VERSION 5.7 ;
  NOWIREEXTENSIONATPIN ON ;
  DIVIDERCHAR "/" ;
  BUSBITCHARS "[]" ;
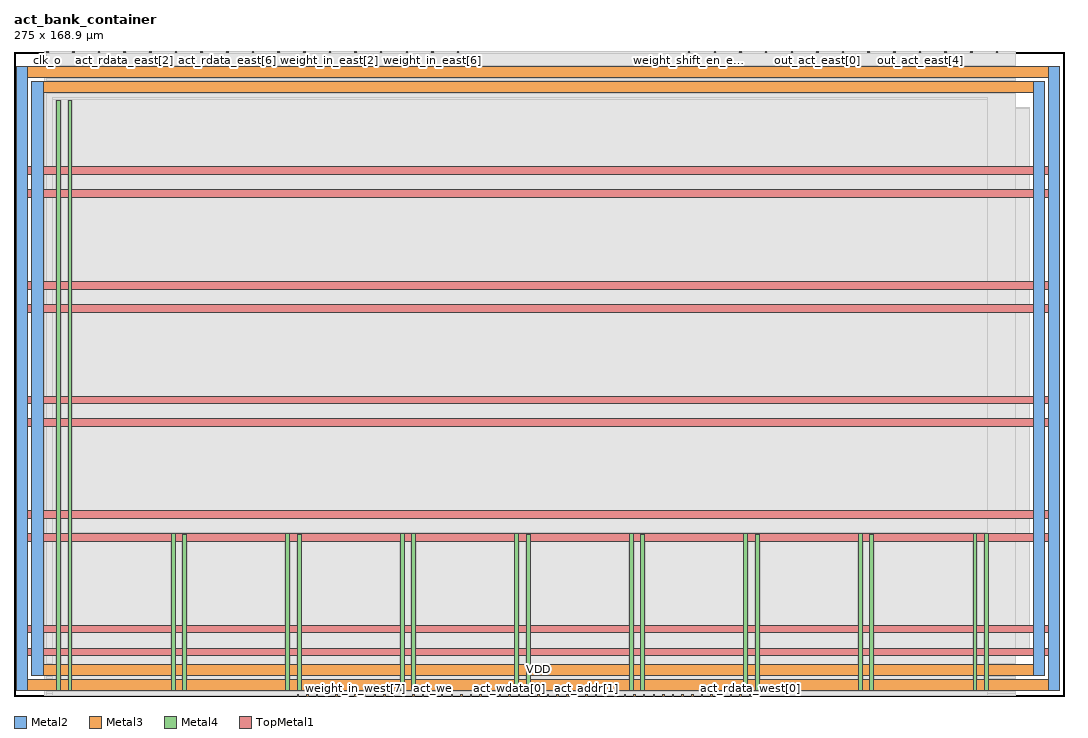
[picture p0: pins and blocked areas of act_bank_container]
MACRO act_bank_container
  CLASS BLOCK ;
  FOREIGN act_bank_container ;
  ORIGIN 0.000 0.000 ;
  SIZE 275.000 BY 168.900 ;
  PIN VDD
    DIRECTION INOUT ;
    USE POWER ;
    PORT
      LAYER Metal2 ;
        RECT 4.640 5.340 7.640 160.980 ;
    END
    PORT
      LAYER Metal2 ;
        RECT 266.920 5.340 269.920 160.980 ;
    END
    PORT
      LAYER Metal3 ;
        RECT 4.640 5.340 269.920 8.340 ;
    END
    PORT
      LAYER Metal3 ;
        RECT 4.640 157.980 269.920 160.980 ;
    END
    PORT
      LAYER Metal4 ;
        RECT 11.180 1.340 12.180 155.960 ;
    END
    PORT
      LAYER Metal4 ;
        RECT 41.180 1.340 42.180 42.560 ;
    END
    PORT
      LAYER Metal4 ;
        RECT 71.180 1.340 72.180 42.560 ;
    END
    PORT
      LAYER Metal4 ;
        RECT 101.180 1.340 102.180 42.560 ;
    END
    PORT
      LAYER Metal4 ;
        RECT 131.180 1.340 132.180 42.560 ;
    END
    PORT
      LAYER Metal4 ;
        RECT 161.180 1.340 162.180 42.660 ;
    END
    PORT
      LAYER Metal4 ;
        RECT 191.180 1.340 192.180 42.560 ;
    END
    PORT
      LAYER Metal4 ;
        RECT 221.180 1.340 222.180 42.560 ;
    END
    PORT
      LAYER Metal4 ;
        RECT 251.180 1.340 252.180 42.660 ;
    END
    PORT
      LAYER TopMetal1 ;
        RECT 0.640 10.560 273.920 12.560 ;
    END
    PORT
      LAYER TopMetal1 ;
        RECT 0.640 40.560 273.920 42.560 ;
    END
    PORT
      LAYER TopMetal1 ;
        RECT 0.640 70.560 273.920 72.560 ;
    END
    PORT
      LAYER TopMetal1 ;
        RECT 0.640 100.560 273.920 102.560 ;
    END
    PORT
      LAYER TopMetal1 ;
        RECT 0.640 130.560 273.920 132.560 ;
    END
  END VDD
  PIN VSS
    DIRECTION INOUT ;
    USE GROUND ;
    PORT
      LAYER Metal2 ;
        RECT 0.640 1.340 3.640 164.980 ;
    END
    PORT
      LAYER Metal2 ;
        RECT 270.920 1.340 273.920 164.980 ;
    END
    PORT
      LAYER Metal3 ;
        RECT 0.640 1.340 273.920 4.340 ;
    END
    PORT
      LAYER Metal3 ;
        RECT 0.640 161.980 273.920 164.980 ;
    END
    PORT
      LAYER Metal4 ;
        RECT 14.180 1.340 15.180 155.960 ;
    END
    PORT
      LAYER Metal4 ;
        RECT 44.180 1.340 45.180 42.420 ;
    END
    PORT
      LAYER Metal4 ;
        RECT 74.180 1.340 75.180 42.420 ;
    END
    PORT
      LAYER Metal4 ;
        RECT 104.180 1.340 105.180 42.660 ;
    END
    PORT
      LAYER Metal4 ;
        RECT 134.180 1.340 135.180 42.420 ;
    END
    PORT
      LAYER Metal4 ;
        RECT 164.180 1.340 165.180 42.420 ;
    END
    PORT
      LAYER Metal4 ;
        RECT 194.180 1.340 195.180 42.420 ;
    END
    PORT
      LAYER Metal4 ;
        RECT 224.180 1.340 225.180 42.420 ;
    END
    PORT
      LAYER Metal4 ;
        RECT 254.180 1.340 255.180 42.660 ;
    END
    PORT
      LAYER TopMetal1 ;
        RECT 0.640 16.560 273.920 18.560 ;
    END
    PORT
      LAYER TopMetal1 ;
        RECT 0.640 46.560 273.920 48.560 ;
    END
    PORT
      LAYER TopMetal1 ;
        RECT 0.640 76.560 273.920 78.560 ;
    END
    PORT
      LAYER TopMetal1 ;
        RECT 0.640 106.560 273.920 108.560 ;
    END
    PORT
      LAYER TopMetal1 ;
        RECT 0.640 136.560 273.920 138.560 ;
    END
  END VSS
  PIN act_addr[0]
    DIRECTION INPUT ;
    USE SIGNAL ;
    ANTENNAGATEAREA 0.109200 ;
    PORT
      LAYER Metal3 ;
        RECT 152.260 0.000 152.660 0.400 ;
    END
  END act_addr[0]
  PIN act_addr[1]
    DIRECTION INPUT ;
    USE SIGNAL ;
    ANTENNAGATEAREA 0.109200 ;
    PORT
      LAYER Metal3 ;
        RECT 149.740 0.000 150.140 0.400 ;
    END
  END act_addr[1]
  PIN act_addr[2]
    DIRECTION INPUT ;
    USE SIGNAL ;
    ANTENNAGATEAREA 0.109200 ;
    PORT
      LAYER Metal3 ;
        RECT 147.220 0.000 147.620 0.400 ;
    END
  END act_addr[2]
  PIN act_addr[3]
    DIRECTION INPUT ;
    USE SIGNAL ;
    ANTENNAGATEAREA 0.109200 ;
    PORT
      LAYER Metal3 ;
        RECT 144.700 0.000 145.100 0.400 ;
    END
  END act_addr[3]
  PIN act_addr[4]
    DIRECTION INPUT ;
    USE SIGNAL ;
    ANTENNAGATEAREA 0.109200 ;
    PORT
      LAYER Metal3 ;
        RECT 142.180 0.000 142.580 0.400 ;
    END
  END act_addr[4]
  PIN act_addr[5]
    DIRECTION INPUT ;
    USE SIGNAL ;
    ANTENNAGATEAREA 0.109200 ;
    PORT
      LAYER Metal3 ;
        RECT 139.660 0.000 140.060 0.400 ;
    END
  END act_addr[5]
  PIN act_addr[6]
    DIRECTION INPUT ;
    USE SIGNAL ;
    ANTENNAGATEAREA 0.109200 ;
    PORT
      LAYER Metal3 ;
        RECT 137.140 0.000 137.540 0.400 ;
    END
  END act_addr[6]
  PIN act_addr[7]
    DIRECTION INPUT ;
    USE SIGNAL ;
    ANTENNAGATEAREA 0.109200 ;
    PORT
      LAYER Metal3 ;
        RECT 134.620 0.000 135.020 0.400 ;
    END
  END act_addr[7]
  PIN act_addr[8]
    DIRECTION INPUT ;
    USE SIGNAL ;
    ANTENNAGATEAREA 0.109200 ;
    PORT
      LAYER Metal3 ;
        RECT 132.100 0.000 132.500 0.400 ;
    END
  END act_addr[8]
  PIN act_rdata_east[0]
    DIRECTION OUTPUT ;
    USE SIGNAL ;
    ANTENNADIFFAREA 0.708600 ;
    PORT
      LAYER Metal3 ;
        RECT 15.340 168.500 15.740 168.900 ;
    END
  END act_rdata_east[0]
  PIN act_rdata_east[1]
    DIRECTION OUTPUT ;
    USE SIGNAL ;
    ANTENNADIFFAREA 0.708600 ;
    PORT
      LAYER Metal3 ;
        RECT 22.060 168.500 22.460 168.900 ;
    END
  END act_rdata_east[1]
  PIN act_rdata_east[2]
    DIRECTION OUTPUT ;
    USE SIGNAL ;
    ANTENNADIFFAREA 0.708600 ;
    PORT
      LAYER Metal3 ;
        RECT 28.780 168.500 29.180 168.900 ;
    END
  END act_rdata_east[2]
  PIN act_rdata_east[3]
    DIRECTION OUTPUT ;
    USE SIGNAL ;
    ANTENNADIFFAREA 0.708600 ;
    PORT
      LAYER Metal3 ;
        RECT 35.500 168.500 35.900 168.900 ;
    END
  END act_rdata_east[3]
  PIN act_rdata_east[4]
    DIRECTION OUTPUT ;
    USE SIGNAL ;
    ANTENNADIFFAREA 0.708600 ;
    PORT
      LAYER Metal3 ;
        RECT 42.220 168.500 42.620 168.900 ;
    END
  END act_rdata_east[4]
  PIN act_rdata_east[5]
    DIRECTION OUTPUT ;
    USE SIGNAL ;
    ANTENNADIFFAREA 0.708600 ;
    PORT
      LAYER Metal3 ;
        RECT 48.940 168.500 49.340 168.900 ;
    END
  END act_rdata_east[5]
  PIN act_rdata_east[6]
    DIRECTION OUTPUT ;
    USE SIGNAL ;
    ANTENNADIFFAREA 0.708600 ;
    PORT
      LAYER Metal3 ;
        RECT 55.660 168.500 56.060 168.900 ;
    END
  END act_rdata_east[6]
  PIN act_rdata_east[7]
    DIRECTION OUTPUT ;
    USE SIGNAL ;
    ANTENNADIFFAREA 0.708600 ;
    PORT
      LAYER Metal3 ;
        RECT 62.380 168.500 62.780 168.900 ;
    END
  END act_rdata_east[7]
  PIN act_rdata_west[0]
    DIRECTION OUTPUT ;
    USE SIGNAL ;
    ANTENNADIFFAREA 0.708600 ;
    PORT
      LAYER Metal3 ;
        RECT 192.580 0.000 192.980 0.400 ;
    END
  END act_rdata_west[0]
  PIN act_rdata_west[1]
    DIRECTION OUTPUT ;
    USE SIGNAL ;
    ANTENNADIFFAREA 0.708600 ;
    PORT
      LAYER Metal3 ;
        RECT 190.060 0.000 190.460 0.400 ;
    END
  END act_rdata_west[1]
  PIN act_rdata_west[2]
    DIRECTION OUTPUT ;
    USE SIGNAL ;
    ANTENNADIFFAREA 0.708600 ;
    PORT
      LAYER Metal3 ;
        RECT 187.540 0.000 187.940 0.400 ;
    END
  END act_rdata_west[2]
  PIN act_rdata_west[3]
    DIRECTION OUTPUT ;
    USE SIGNAL ;
    ANTENNADIFFAREA 0.708600 ;
    PORT
      LAYER Metal3 ;
        RECT 185.020 0.000 185.420 0.400 ;
    END
  END act_rdata_west[3]
  PIN act_rdata_west[4]
    DIRECTION OUTPUT ;
    USE SIGNAL ;
    ANTENNADIFFAREA 0.708600 ;
    PORT
      LAYER Metal3 ;
        RECT 182.500 0.000 182.900 0.400 ;
    END
  END act_rdata_west[4]
  PIN act_rdata_west[5]
    DIRECTION OUTPUT ;
    USE SIGNAL ;
    ANTENNADIFFAREA 0.708600 ;
    PORT
      LAYER Metal3 ;
        RECT 179.980 0.000 180.380 0.400 ;
    END
  END act_rdata_west[5]
  PIN act_rdata_west[6]
    DIRECTION OUTPUT ;
    USE SIGNAL ;
    ANTENNADIFFAREA 0.708600 ;
    PORT
      LAYER Metal3 ;
        RECT 177.460 0.000 177.860 0.400 ;
    END
  END act_rdata_west[6]
  PIN act_rdata_west[7]
    DIRECTION OUTPUT ;
    USE SIGNAL ;
    ANTENNADIFFAREA 0.708600 ;
    PORT
      LAYER Metal3 ;
        RECT 174.940 0.000 175.340 0.400 ;
    END
  END act_rdata_west[7]
  PIN act_wdata[0]
    DIRECTION INPUT ;
    USE SIGNAL ;
    ANTENNAGATEAREA 0.109200 ;
    PORT
      LAYER Metal3 ;
        RECT 129.580 0.000 129.980 0.400 ;
    END
  END act_wdata[0]
  PIN act_wdata[1]
    DIRECTION INPUT ;
    USE SIGNAL ;
    ANTENNAGATEAREA 0.109200 ;
    PORT
      LAYER Metal3 ;
        RECT 127.060 0.000 127.460 0.400 ;
    END
  END act_wdata[1]
  PIN act_wdata[2]
    DIRECTION INPUT ;
    USE SIGNAL ;
    ANTENNAGATEAREA 0.109200 ;
    PORT
      LAYER Metal3 ;
        RECT 124.540 0.000 124.940 0.400 ;
    END
  END act_wdata[2]
  PIN act_wdata[3]
    DIRECTION INPUT ;
    USE SIGNAL ;
    ANTENNAGATEAREA 0.109200 ;
    PORT
      LAYER Metal3 ;
        RECT 122.020 0.000 122.420 0.400 ;
    END
  END act_wdata[3]
  PIN act_wdata[4]
    DIRECTION INPUT ;
    USE SIGNAL ;
    ANTENNAGATEAREA 0.109200 ;
    PORT
      LAYER Metal3 ;
        RECT 119.500 0.000 119.900 0.400 ;
    END
  END act_wdata[4]
  PIN act_wdata[5]
    DIRECTION INPUT ;
    USE SIGNAL ;
    ANTENNAGATEAREA 0.109200 ;
    PORT
      LAYER Metal3 ;
        RECT 116.980 0.000 117.380 0.400 ;
    END
  END act_wdata[5]
  PIN act_wdata[6]
    DIRECTION INPUT ;
    USE SIGNAL ;
    ANTENNAGATEAREA 0.109200 ;
    PORT
      LAYER Metal3 ;
        RECT 114.460 0.000 114.860 0.400 ;
    END
  END act_wdata[6]
  PIN act_wdata[7]
    DIRECTION INPUT ;
    USE SIGNAL ;
    ANTENNAGATEAREA 0.109200 ;
    PORT
      LAYER Metal3 ;
        RECT 111.940 0.000 112.340 0.400 ;
    END
  END act_wdata[7]
  PIN act_we
    DIRECTION INPUT ;
    USE SIGNAL ;
    ANTENNAGATEAREA 0.109200 ;
    PORT
      LAYER Metal3 ;
        RECT 109.420 0.000 109.820 0.400 ;
    END
  END act_we
  PIN clk_i
    DIRECTION INPUT ;
    USE SIGNAL ;
    ANTENNAGATEAREA 0.381550 ;
    PORT
      LAYER Metal3 ;
        RECT 74.140 0.000 74.540 0.400 ;
    END
  END clk_i
  PIN clk_o
    DIRECTION OUTPUT ;
    USE SIGNAL ;
    ANTENNADIFFAREA 0.708600 ;
    PORT
      LAYER Metal3 ;
        RECT 8.620 168.500 9.020 168.900 ;
    END
  END clk_o
  PIN out_act_east[0]
    DIRECTION INPUT ;
    USE SIGNAL ;
    ANTENNAGATEAREA 0.180700 ;
    PORT
      LAYER Metal3 ;
        RECT 210.220 168.500 210.620 168.900 ;
    END
  END out_act_east[0]
  PIN out_act_east[1]
    DIRECTION INPUT ;
    USE SIGNAL ;
    ANTENNAGATEAREA 0.180700 ;
    PORT
      LAYER Metal3 ;
        RECT 216.940 168.500 217.340 168.900 ;
    END
  END out_act_east[1]
  PIN out_act_east[2]
    DIRECTION INPUT ;
    USE SIGNAL ;
    ANTENNAGATEAREA 0.180700 ;
    ANTENNADIFFAREA 2.015400 ;
    PORT
      LAYER Metal3 ;
        RECT 223.660 168.500 224.060 168.900 ;
    END
  END out_act_east[2]
  PIN out_act_east[3]
    DIRECTION INPUT ;
    USE SIGNAL ;
    ANTENNAGATEAREA 0.180700 ;
    PORT
      LAYER Metal3 ;
        RECT 230.380 168.500 230.780 168.900 ;
    END
  END out_act_east[3]
  PIN out_act_east[4]
    DIRECTION INPUT ;
    USE SIGNAL ;
    ANTENNAGATEAREA 0.180700 ;
    PORT
      LAYER Metal3 ;
        RECT 237.100 168.500 237.500 168.900 ;
    END
  END out_act_east[4]
  PIN out_act_east[5]
    DIRECTION INPUT ;
    USE SIGNAL ;
    ANTENNAGATEAREA 0.180700 ;
    PORT
      LAYER Metal3 ;
        RECT 243.820 168.500 244.220 168.900 ;
    END
  END out_act_east[5]
  PIN out_act_east[6]
    DIRECTION INPUT ;
    USE SIGNAL ;
    ANTENNAGATEAREA 0.180700 ;
    PORT
      LAYER Metal3 ;
        RECT 250.540 168.500 250.940 168.900 ;
    END
  END out_act_east[6]
  PIN out_act_east[7]
    DIRECTION INPUT ;
    USE SIGNAL ;
    ANTENNAGATEAREA 0.180700 ;
    PORT
      LAYER Metal3 ;
        RECT 257.260 168.500 257.660 168.900 ;
    END
  END out_act_east[7]
  PIN out_act_west[0]
    DIRECTION OUTPUT ;
    USE SIGNAL ;
    ANTENNADIFFAREA 0.708600 ;
    PORT
      LAYER Metal3 ;
        RECT 172.420 0.000 172.820 0.400 ;
    END
  END out_act_west[0]
  PIN out_act_west[1]
    DIRECTION OUTPUT ;
    USE SIGNAL ;
    ANTENNADIFFAREA 0.708600 ;
    PORT
      LAYER Metal3 ;
        RECT 169.900 0.000 170.300 0.400 ;
    END
  END out_act_west[1]
  PIN out_act_west[2]
    DIRECTION OUTPUT ;
    USE SIGNAL ;
    ANTENNADIFFAREA 0.708600 ;
    PORT
      LAYER Metal3 ;
        RECT 167.380 0.000 167.780 0.400 ;
    END
  END out_act_west[2]
  PIN out_act_west[3]
    DIRECTION OUTPUT ;
    USE SIGNAL ;
    ANTENNADIFFAREA 0.708600 ;
    PORT
      LAYER Metal3 ;
        RECT 164.860 0.000 165.260 0.400 ;
    END
  END out_act_west[3]
  PIN out_act_west[4]
    DIRECTION OUTPUT ;
    USE SIGNAL ;
    ANTENNADIFFAREA 0.708600 ;
    PORT
      LAYER Metal3 ;
        RECT 162.340 0.000 162.740 0.400 ;
    END
  END out_act_west[4]
  PIN out_act_west[5]
    DIRECTION OUTPUT ;
    USE SIGNAL ;
    ANTENNADIFFAREA 0.708600 ;
    PORT
      LAYER Metal3 ;
        RECT 159.820 0.000 160.220 0.400 ;
    END
  END out_act_west[5]
  PIN out_act_west[6]
    DIRECTION OUTPUT ;
    USE SIGNAL ;
    ANTENNADIFFAREA 0.708600 ;
    PORT
      LAYER Metal3 ;
        RECT 157.300 0.000 157.700 0.400 ;
    END
  END out_act_west[6]
  PIN out_act_west[7]
    DIRECTION OUTPUT ;
    USE SIGNAL ;
    ANTENNADIFFAREA 0.708600 ;
    PORT
      LAYER Metal3 ;
        RECT 154.780 0.000 155.180 0.400 ;
    END
  END out_act_west[7]
  PIN weight_in_east[0]
    DIRECTION OUTPUT ;
    USE SIGNAL ;
    ANTENNADIFFAREA 0.708600 ;
    PORT
      LAYER Metal3 ;
        RECT 69.100 168.500 69.500 168.900 ;
    END
  END weight_in_east[0]
  PIN weight_in_east[1]
    DIRECTION OUTPUT ;
    USE SIGNAL ;
    ANTENNADIFFAREA 0.708600 ;
    PORT
      LAYER Metal3 ;
        RECT 75.820 168.500 76.220 168.900 ;
    END
  END weight_in_east[1]
  PIN weight_in_east[2]
    DIRECTION OUTPUT ;
    USE SIGNAL ;
    ANTENNADIFFAREA 0.708600 ;
    PORT
      LAYER Metal3 ;
        RECT 82.540 168.500 82.940 168.900 ;
    END
  END weight_in_east[2]
  PIN weight_in_east[3]
    DIRECTION OUTPUT ;
    USE SIGNAL ;
    ANTENNADIFFAREA 0.708600 ;
    PORT
      LAYER Metal3 ;
        RECT 89.260 168.500 89.660 168.900 ;
    END
  END weight_in_east[3]
  PIN weight_in_east[4]
    DIRECTION OUTPUT ;
    USE SIGNAL ;
    ANTENNADIFFAREA 0.708600 ;
    PORT
      LAYER Metal3 ;
        RECT 95.980 168.500 96.380 168.900 ;
    END
  END weight_in_east[4]
  PIN weight_in_east[5]
    DIRECTION OUTPUT ;
    USE SIGNAL ;
    ANTENNADIFFAREA 0.708600 ;
    PORT
      LAYER Metal3 ;
        RECT 102.700 168.500 103.100 168.900 ;
    END
  END weight_in_east[5]
  PIN weight_in_east[6]
    DIRECTION OUTPUT ;
    USE SIGNAL ;
    ANTENNADIFFAREA 0.708600 ;
    PORT
      LAYER Metal3 ;
        RECT 109.420 168.500 109.820 168.900 ;
    END
  END weight_in_east[6]
  PIN weight_in_east[7]
    DIRECTION OUTPUT ;
    USE SIGNAL ;
    ANTENNADIFFAREA 0.708600 ;
    PORT
      LAYER Metal3 ;
        RECT 116.140 168.500 116.540 168.900 ;
    END
  END weight_in_east[7]
  PIN weight_in_west[0]
    DIRECTION INPUT ;
    USE SIGNAL ;
    ANTENNAGATEAREA 0.180700 ;
    PORT
      LAYER Metal3 ;
        RECT 106.900 0.000 107.300 0.400 ;
    END
  END weight_in_west[0]
  PIN weight_in_west[1]
    DIRECTION INPUT ;
    USE SIGNAL ;
    ANTENNAGATEAREA 0.180700 ;
    PORT
      LAYER Metal3 ;
        RECT 104.380 0.000 104.780 0.400 ;
    END
  END weight_in_west[1]
  PIN weight_in_west[2]
    DIRECTION INPUT ;
    USE SIGNAL ;
    ANTENNAGATEAREA 0.180700 ;
    PORT
      LAYER Metal3 ;
        RECT 101.860 0.000 102.260 0.400 ;
    END
  END weight_in_west[2]
  PIN weight_in_west[3]
    DIRECTION INPUT ;
    USE SIGNAL ;
    ANTENNAGATEAREA 0.180700 ;
    PORT
      LAYER Metal3 ;
        RECT 99.340 0.000 99.740 0.400 ;
    END
  END weight_in_west[3]
  PIN weight_in_west[4]
    DIRECTION INPUT ;
    USE SIGNAL ;
    ANTENNAGATEAREA 0.180700 ;
    PORT
      LAYER Metal3 ;
        RECT 96.820 0.000 97.220 0.400 ;
    END
  END weight_in_west[4]
  PIN weight_in_west[5]
    DIRECTION INPUT ;
    USE SIGNAL ;
    ANTENNAGATEAREA 0.180700 ;
    PORT
      LAYER Metal3 ;
        RECT 94.300 0.000 94.700 0.400 ;
    END
  END weight_in_west[5]
  PIN weight_in_west[6]
    DIRECTION INPUT ;
    USE SIGNAL ;
    ANTENNAGATEAREA 0.180700 ;
    PORT
      LAYER Metal3 ;
        RECT 91.780 0.000 92.180 0.400 ;
    END
  END weight_in_west[6]
  PIN weight_in_west[7]
    DIRECTION INPUT ;
    USE SIGNAL ;
    ANTENNAGATEAREA 0.180700 ;
    PORT
      LAYER Metal3 ;
        RECT 89.260 0.000 89.660 0.400 ;
    END
  END weight_in_west[7]
  PIN weight_shift_en_east
    DIRECTION OUTPUT ;
    USE SIGNAL ;
    ANTENNADIFFAREA 0.708600 ;
    PORT
      LAYER Metal3 ;
        RECT 176.620 168.500 177.020 168.900 ;
    END
  END weight_shift_en_east
  PIN weight_shift_en_west
    DIRECTION INPUT ;
    USE SIGNAL ;
    ANTENNAGATEAREA 0.180700 ;
    PORT
      LAYER Metal3 ;
        RECT 86.740 0.000 87.140 0.400 ;
    END
  END weight_shift_en_west
  PIN xbar_sel_east[0]
    DIRECTION OUTPUT ;
    USE SIGNAL ;
    ANTENNADIFFAREA 0.708600 ;
    PORT
      LAYER Metal3 ;
        RECT 183.340 168.500 183.740 168.900 ;
    END
  END xbar_sel_east[0]
  PIN xbar_sel_east[1]
    DIRECTION OUTPUT ;
    USE SIGNAL ;
    ANTENNADIFFAREA 0.708600 ;
    PORT
      LAYER Metal3 ;
        RECT 190.060 168.500 190.460 168.900 ;
    END
  END xbar_sel_east[1]
  PIN xbar_sel_east[2]
    DIRECTION OUTPUT ;
    USE SIGNAL ;
    ANTENNADIFFAREA 0.708600 ;
    PORT
      LAYER Metal3 ;
        RECT 196.780 168.500 197.180 168.900 ;
    END
  END xbar_sel_east[2]
  PIN xbar_sel_east[3]
    DIRECTION OUTPUT ;
    USE SIGNAL ;
    ANTENNADIFFAREA 0.708600 ;
    PORT
      LAYER Metal3 ;
        RECT 203.500 168.500 203.900 168.900 ;
    END
  END xbar_sel_east[3]
  PIN xbar_sel_west[0]
    DIRECTION INPUT ;
    USE SIGNAL ;
    ANTENNAGATEAREA 0.180700 ;
    PORT
      LAYER Metal3 ;
        RECT 84.220 0.000 84.620 0.400 ;
    END
  END xbar_sel_west[0]
  PIN xbar_sel_west[1]
    DIRECTION INPUT ;
    USE SIGNAL ;
    ANTENNAGATEAREA 0.180700 ;
    PORT
      LAYER Metal3 ;
        RECT 81.700 0.000 82.100 0.400 ;
    END
  END xbar_sel_west[1]
  PIN xbar_sel_west[2]
    DIRECTION INPUT ;
    USE SIGNAL ;
    ANTENNAGATEAREA 0.180700 ;
    PORT
      LAYER Metal3 ;
        RECT 79.180 0.000 79.580 0.400 ;
    END
  END xbar_sel_west[2]
  PIN xbar_sel_west[3]
    DIRECTION INPUT ;
    USE SIGNAL ;
    ANTENNAGATEAREA 0.180700 ;
    PORT
      LAYER Metal3 ;
        RECT 76.660 0.000 77.060 0.400 ;
    END
  END xbar_sel_west[3]
  OBS
      LAYER GatPoly ;
        RECT 8.640 11.190 265.920 154.040 ;
      LAYER Metal1 ;
        RECT 8.640 11.120 265.920 153.995 ;
      LAYER Metal2 ;
        RECT 8.060 0.055 262.185 168.845 ;
      LAYER Metal3 ;
        RECT 9.230 168.290 15.130 168.800 ;
        RECT 15.950 168.290 21.850 168.800 ;
        RECT 22.670 168.290 28.570 168.800 ;
        RECT 29.390 168.290 35.290 168.800 ;
        RECT 36.110 168.290 42.010 168.800 ;
        RECT 42.830 168.290 48.730 168.800 ;
        RECT 49.550 168.290 55.450 168.800 ;
        RECT 56.270 168.290 62.170 168.800 ;
        RECT 62.990 168.290 68.890 168.800 ;
        RECT 69.710 168.290 75.610 168.800 ;
        RECT 76.430 168.290 82.330 168.800 ;
        RECT 83.150 168.290 89.050 168.800 ;
        RECT 89.870 168.290 95.770 168.800 ;
        RECT 96.590 168.290 102.490 168.800 ;
        RECT 103.310 168.290 109.210 168.800 ;
        RECT 110.030 168.290 115.930 168.800 ;
        RECT 116.750 168.290 176.410 168.800 ;
        RECT 177.230 168.290 183.130 168.800 ;
        RECT 183.950 168.290 189.850 168.800 ;
        RECT 190.670 168.290 196.570 168.800 ;
        RECT 197.390 168.290 203.290 168.800 ;
        RECT 204.110 168.290 210.010 168.800 ;
        RECT 210.830 168.290 216.730 168.800 ;
        RECT 217.550 168.290 223.450 168.800 ;
        RECT 224.270 168.290 230.170 168.800 ;
        RECT 230.990 168.290 236.890 168.800 ;
        RECT 237.710 168.290 243.610 168.800 ;
        RECT 244.430 168.290 250.330 168.800 ;
        RECT 251.150 168.290 257.050 168.800 ;
        RECT 257.870 168.290 262.225 168.800 ;
        RECT 8.495 165.190 262.225 168.290 ;
        RECT 8.495 161.190 262.225 161.770 ;
        RECT 8.495 8.550 262.225 157.770 ;
        RECT 8.495 4.550 262.225 5.130 ;
        RECT 8.495 0.610 262.225 1.130 ;
        RECT 8.495 0.095 73.930 0.610 ;
        RECT 74.750 0.095 76.450 0.610 ;
        RECT 77.270 0.095 78.970 0.610 ;
        RECT 79.790 0.095 81.490 0.610 ;
        RECT 82.310 0.095 84.010 0.610 ;
        RECT 84.830 0.095 86.530 0.610 ;
        RECT 87.350 0.095 89.050 0.610 ;
        RECT 89.870 0.095 91.570 0.610 ;
        RECT 92.390 0.095 94.090 0.610 ;
        RECT 94.910 0.095 96.610 0.610 ;
        RECT 97.430 0.095 99.130 0.610 ;
        RECT 99.950 0.095 101.650 0.610 ;
        RECT 102.470 0.095 104.170 0.610 ;
        RECT 104.990 0.095 106.690 0.610 ;
        RECT 107.510 0.095 109.210 0.610 ;
        RECT 110.030 0.095 111.730 0.610 ;
        RECT 112.550 0.095 114.250 0.610 ;
        RECT 115.070 0.095 116.770 0.610 ;
        RECT 117.590 0.095 119.290 0.610 ;
        RECT 120.110 0.095 121.810 0.610 ;
        RECT 122.630 0.095 124.330 0.610 ;
        RECT 125.150 0.095 126.850 0.610 ;
        RECT 127.670 0.095 129.370 0.610 ;
        RECT 130.190 0.095 131.890 0.610 ;
        RECT 132.710 0.095 134.410 0.610 ;
        RECT 135.230 0.095 136.930 0.610 ;
        RECT 137.750 0.095 139.450 0.610 ;
        RECT 140.270 0.095 141.970 0.610 ;
        RECT 142.790 0.095 144.490 0.610 ;
        RECT 145.310 0.095 147.010 0.610 ;
        RECT 147.830 0.095 149.530 0.610 ;
        RECT 150.350 0.095 152.050 0.610 ;
        RECT 152.870 0.095 154.570 0.610 ;
        RECT 155.390 0.095 157.090 0.610 ;
        RECT 157.910 0.095 159.610 0.610 ;
        RECT 160.430 0.095 162.130 0.610 ;
        RECT 162.950 0.095 164.650 0.610 ;
        RECT 165.470 0.095 167.170 0.610 ;
        RECT 167.990 0.095 169.690 0.610 ;
        RECT 170.510 0.095 172.210 0.610 ;
        RECT 173.030 0.095 174.730 0.610 ;
        RECT 175.550 0.095 177.250 0.610 ;
        RECT 178.070 0.095 179.770 0.610 ;
        RECT 180.590 0.095 182.290 0.610 ;
        RECT 183.110 0.095 184.810 0.610 ;
        RECT 185.630 0.095 187.330 0.610 ;
        RECT 188.150 0.095 189.850 0.610 ;
        RECT 190.670 0.095 192.370 0.610 ;
        RECT 193.190 0.095 262.225 0.610 ;
      LAYER Metal4 ;
        RECT 9.980 156.170 254.980 156.805 ;
        RECT 9.980 1.130 10.970 156.170 ;
        RECT 12.390 1.130 13.970 156.170 ;
        RECT 15.390 42.870 254.980 156.170 ;
        RECT 15.390 42.770 103.970 42.870 ;
        RECT 15.390 1.130 40.970 42.770 ;
        RECT 42.390 42.630 70.970 42.770 ;
        RECT 42.390 1.130 43.970 42.630 ;
        RECT 45.390 1.130 70.970 42.630 ;
        RECT 72.390 42.630 100.970 42.770 ;
        RECT 72.390 1.130 73.970 42.630 ;
        RECT 75.390 1.130 100.970 42.630 ;
        RECT 102.390 1.130 103.970 42.770 ;
        RECT 105.390 42.770 160.970 42.870 ;
        RECT 105.390 1.130 130.970 42.770 ;
        RECT 132.390 42.630 160.970 42.770 ;
        RECT 132.390 1.130 133.970 42.630 ;
        RECT 135.390 1.130 160.970 42.630 ;
        RECT 162.390 42.770 250.970 42.870 ;
        RECT 162.390 42.630 190.970 42.770 ;
        RECT 162.390 1.130 163.970 42.630 ;
        RECT 165.390 1.130 190.970 42.630 ;
        RECT 192.390 42.630 220.970 42.770 ;
        RECT 192.390 1.130 193.970 42.630 ;
        RECT 195.390 1.130 220.970 42.630 ;
        RECT 222.390 42.630 250.970 42.770 ;
        RECT 222.390 1.130 223.970 42.630 ;
        RECT 225.390 1.130 250.970 42.630 ;
        RECT 252.390 1.130 253.970 42.870 ;
        RECT 9.980 0.055 254.980 1.130 ;
  END
END act_bank_container
END LIBRARY

